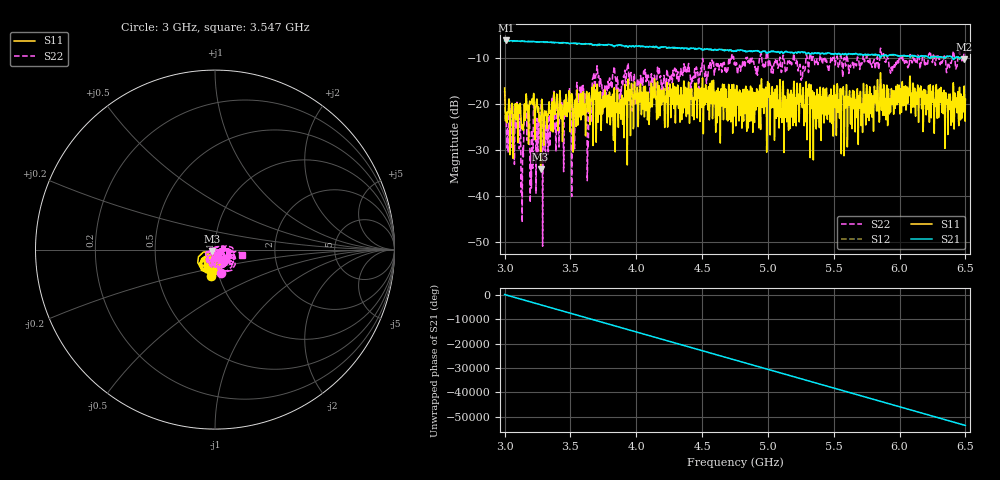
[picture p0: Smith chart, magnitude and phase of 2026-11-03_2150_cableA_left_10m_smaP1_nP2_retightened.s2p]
! HEWLETT PACKARD,8720ES,MY41003347,7.72, via bringup/vna_tests.py
! cableA_left_10m_smaP1_nP2_retightened
! measured 2026-11-03 21:51:00, 1601 points, 3000000000-6500000000 Hz, IF bandwidth 1000 Hz, source -40.00 dBm, kit CALK35MD
# HZ S RI R 50
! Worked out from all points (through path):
!   1601 points, 3 GHz to 6.5 GHz, reference 50 ohm
!   highest |S21| = -6.29 dB at 3.013 GHz (marker M1); lowest = -10.4 dB at 6.491 GHz (marker M2)
!   lowest |S11| = -34.3 dB at 3.273 GHz (marker M3), VSWR 1.04, Z = 48.3 - j0.915 ohm
!   |S11| at or under -10 dB: start of sweep to end of sweep
!   |S22| runs from -51.0 to -8.0 dB; largest |S21 - S12| = 0.011
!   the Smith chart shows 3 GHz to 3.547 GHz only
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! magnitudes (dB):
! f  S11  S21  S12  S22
! 3 GHz  -16.6  -6.4  -6.5  -17.3
! 3.013 GHz  -21.8  -6.3  -6.3  -23.6
! 3.103 GHz  -23.7  -6.4  -6.4  -21.1
! 3.127 GHz  -24.5  -6.4  -6.5  -39.4
! 3.164 GHz  -17.9  -6.5  -6.6  -19.2
! 3.199 GHz  -20.0  -6.5  -6.6  -30.4
! 3.273 GHz  -34.3  -6.6  -6.6  -20.9
! 3.304 GHz  -21.6  -6.6  -6.7  -23.8
! 3.365 GHz  -23.5  -6.7  -6.8  -19.7
! 3.398 GHz  -18.1  -6.8  -6.9  -19.2
! 3.483 GHz  -21.8  -6.9  -6.9  -22.1
! 3.523 GHz  -29.4  -6.9  -7.0  -21.7
! 3.584 GHz  -18.1  -7.1  -7.1  -16.1
! 3.643 GHz  -17.7  -7.0  -7.2  -18.2
! 3.689 GHz  -17.3  -7.3  -7.3  -15.2
! 3.759 GHz  -18.3  -7.3  -7.3  -17.2
! 4.168 GHz  -23.1  -7.8  -7.8  -13.5
! 4.75 GHz  -17.0  -8.6  -8.5  -11.0
! 5.334 GHz  -21.1  -9.0  -9.1  -11.0
! 5.918 GHz  -18.2  -9.6  -9.6  -11.3
! 6.491 GHz  -16.2  -10.4  -10.3  -8.7
! 6.5 GHz  -19.0  -10.3  -10.2  -8.9
